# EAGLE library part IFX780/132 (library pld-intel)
PLD

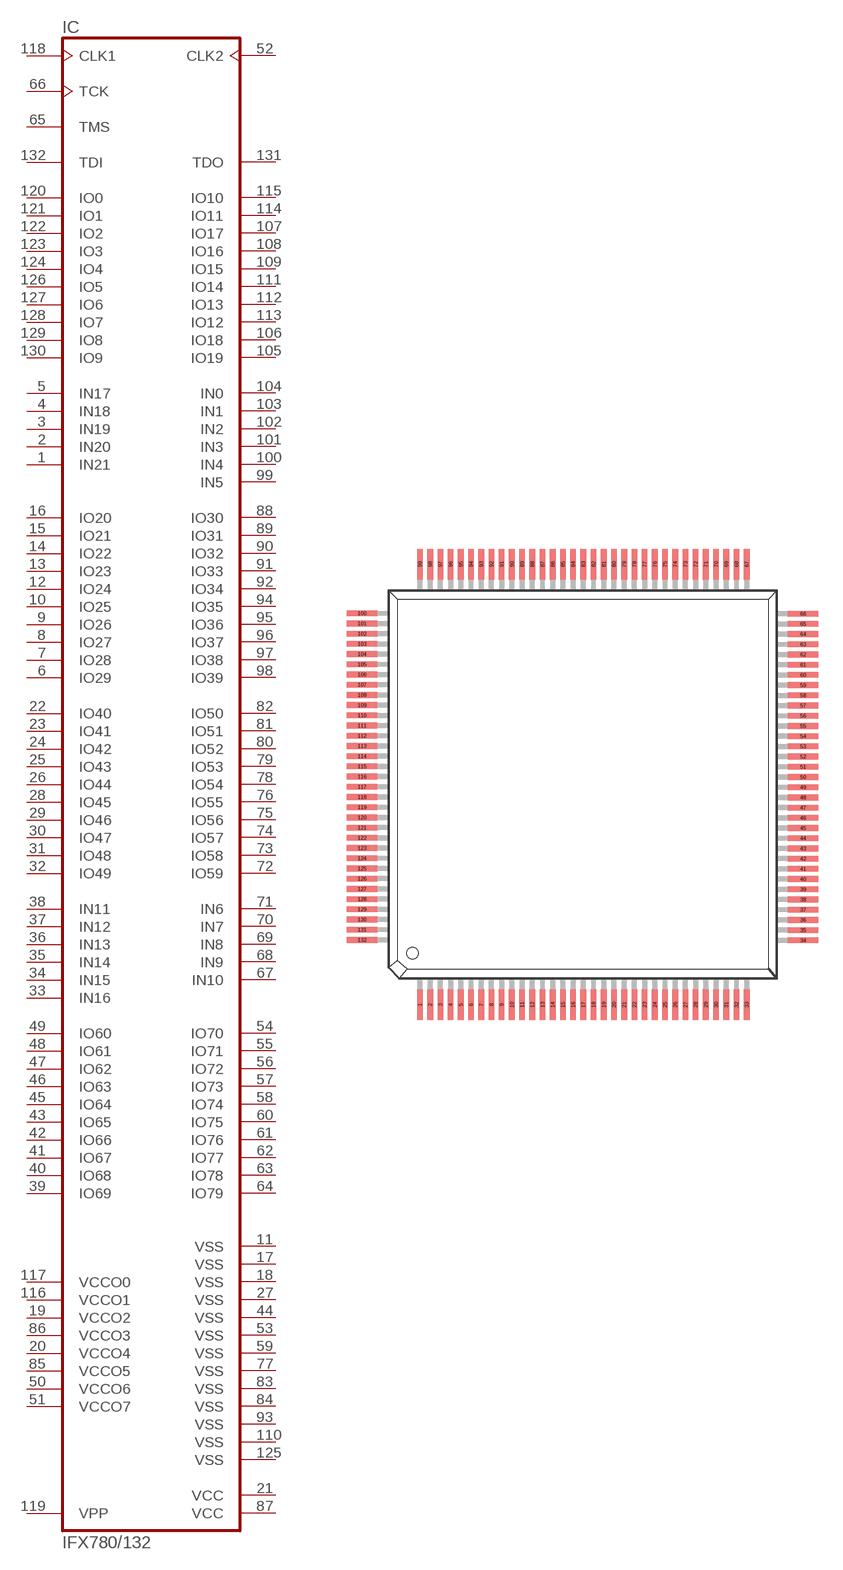
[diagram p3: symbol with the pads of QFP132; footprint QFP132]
Designator prefix IC

## IFX780/132 (OC_FARNELL: unknown; OC_NEWARK: unknown)  [QFP132]
1  IN21  in
2  IN20  in
3  IN19  in
4  IN18  in
5  IN17  in
6  IO29
7  IO28
8  IO27
9  IO26
10  IO25
11  VSS  pwr
12  IO24
13  IO23
14  IO22
15  IO21
16  IO20
17  VSS  pwr
18  VSS  pwr
19  VCCO2  sup
20  VCCO4  sup
21  VCC  pwr
22  IO40
23  IO41
24  IO42
25  IO43
26  IO44
27  VSS  pwr
28  IO45
29  IO46
30  IO47
31  IO48
32  IO49
33  IN16  in
34  IN15  in
35  IN14  in
36  IN13  in
37  IN12  in
38  IN11  in
39  IO69
40  IO68
41  IO67
42  IO66
43  IO65
44  VSS  pwr
45  IO64
46  IO63
47  IO62
48  IO61
49  IO60
50  VCCO6  sup
51  VCCO7  sup
52  CLK2  in
53  VSS  pwr
54  IO70
55  IO71
56  IO72
57  IO73
58  IO74
59  VSS  pwr
60  IO75
61  IO76
62  IO77
63  IO78
64  IO79
65  TMS  in
66  TCK  in
67  IN10  in
68  IN9  in
69  IN8  in
70  IN7  in
71  IN6  in
72  IO59
73  IO58
74  IO57
75  IO56
76  IO55
77  VSS  pwr
78  IO54
79  IO53
80  IO52
81  IO51
82  IO50
83  VSS  pwr
84  VSS  pwr
85  VCCO5  sup
86  VCCO3  sup
87  VCC  pwr
88  IO30
89  IO31
90  IO32
91  IO33
92  IO34
93  VSS  pwr
94  IO35
95  IO36
96  IO37
97  IO38
98  IO39
99  IN5  in
100  IN4  in
101  IN3  in
102  IN2  in
103  IN1  in
104  IN0  in
105  IO19
106  IO18
107  IO17
108  IO16
109  IO15
110  VSS  pwr
111  IO14
112  IO13
113  IO12
114  IO11
115  IO10
116  VCCO1  sup
117  VCCO0  sup
118  CLK1  in
119  VPP  sup
120  IO0
121  IO1
122  IO2
123  IO3
124  IO4
125  VSS  pwr
126  IO5
127  IO6
128  IO7
129  IO8
130  IO9
131  TDO  out
132  TDI  in

## Footprint QFP132 (pad centres in mm)
Quad Flat Pack
smd 0.356 x 1.905: 1 -10.211,-13.64; 2 -9.576,-13.64; 3 -8.941,-13.64; 4 -8.306,-13.64; 5 -7.671,-13.64; 6 -7.036,-13.64; 7 -6.401,-13.64; 8 -5.766,-13.64; 9 -5.131,-13.64; 10 -4.496,-13.64; 11 -3.861,-13.64; 12 -3.226,-13.64; 13 -2.591,-13.64; 14 -1.956,-13.64; 15 -1.321,-13.64; 16 -0.686,-13.64; 17 -0.051,-13.64; 18 0.584,-13.64; 19 1.219,-13.64; 20 1.854,-13.64; 21 2.489,-13.64; 22 3.124,-13.64; 23 3.759,-13.64; 24 4.394,-13.64; 25 5.029,-13.64; 26 5.664,-13.64; 27 6.299,-13.64; 28 6.934,-13.64; 29 7.569,-13.64; 30 8.204,-13.64; 31 8.839,-13.64; 32 9.474,-13.64; 33 10.109,-13.64; 67 10.109,13.767; 68 9.474,13.767; 69 8.839,13.767; 70 8.204,13.767; 71 7.569,13.767; 72 6.934,13.767; 73 6.299,13.767; 74 5.664,13.767; 75 5.029,13.767; 76 4.394,13.767; 77 3.759,13.767; 78 3.124,13.767; 79 2.489,13.767; 80 1.854,13.767; 81 1.219,13.767; 82 0.584,13.767; 83 -0.051,13.767; 84 -0.686,13.767; 85 -1.321,13.767; 86 -1.956,13.767; 87 -2.591,13.767; 88 -3.226,13.767; 89 -3.861,13.767; 90 -4.496,13.767; 91 -5.131,13.767; 92 -5.766,13.767; 93 -6.401,13.767; 94 -7.036,13.767; 95 -7.671,13.767; 96 -8.306,13.767; 97 -8.941,13.767; 98 -9.576,13.767; 99 -10.211,13.767
smd 1.905 x 0.356: 34 13.614,-9.627; 35 13.614,-8.992; 36 13.614,-8.357; 37 13.614,-7.722; 38 13.614,-7.087; 39 13.614,-6.452; 40 13.614,-5.817; 41 13.614,-5.182; 42 13.614,-4.547; 43 13.614,-3.912; 44 13.614,-3.277; 45 13.614,-2.642; 46 13.614,-2.007; 47 13.614,-1.372; 48 13.614,-0.737; 49 13.614,-0.102; 50 13.614,0.533; 51 13.614,1.168; 52 13.614,1.803; 53 13.614,2.438; 54 13.614,3.073; 55 13.614,3.708; 56 13.614,4.343; 57 13.614,4.978; 58 13.614,5.613; 59 13.614,6.248; 60 13.614,6.883; 61 13.614,7.518; 62 13.614,8.153; 63 13.614,8.788; 64 13.614,9.423; 65 13.614,10.058; 66 13.614,10.693; 100 -13.818,10.719; 101 -13.818,10.084; 102 -13.818,9.449; 103 -13.818,8.814; 104 -13.818,8.179; 105 -13.818,7.544; 106 -13.818,6.909; 107 -13.818,6.274; 108 -13.818,5.639; 109 -13.818,5.004; 110 -13.818,4.369; 111 -13.818,3.734; 112 -13.818,3.099; 113 -13.818,2.464; 114 -13.818,1.829; 115 -13.818,1.194; 116 -13.818,0.559; 117 -13.818,-0.076; 118 -13.818,-0.711; 119 -13.818,-1.346; 120 -13.818,-1.981; 121 -13.818,-2.616; 122 -13.818,-3.251; 123 -13.818,-3.886; 124 -13.818,-4.521; 125 -13.818,-5.156; 126 -13.818,-5.791; 127 -13.818,-6.426; 128 -13.818,-7.061; 129 -13.818,-7.696; 130 -13.818,-8.331; 131 -13.818,-8.966; 132 -13.818,-9.601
